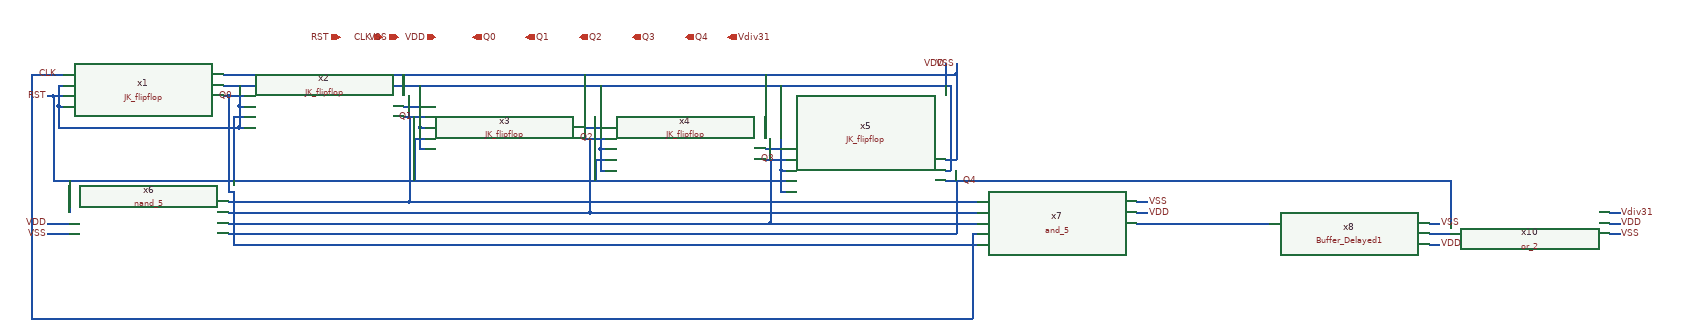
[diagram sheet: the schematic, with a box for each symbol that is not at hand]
v {xschem version=3.1.0 file_version=1.2
}
G {}
K {}
V {}
S {}
E {}
N 230 -20 260 -20 {
lab=Q0}
N 560 20 600 20 {
lab=Q1}
N 900 60 940 60 {
lab=Q2}
N 1240 100 1280 100 {
lab=Q3}
N 1270 120 1280 120 {
lab=VDD}
N 1270 120 1270 160 {
lab=VDD}
N 1270 160 1280 160 {
lab=VDD}
N 930 80 940 80 {
lab=VDD}
N 930 80 930 120 {
lab=VDD}
N 930 120 940 120 {
lab=VDD}
N 590 40 600 40 {
lab=VDD}
N 590 40 590 80 {
lab=VDD}
N 590 80 600 80 {
lab=VDD}
N 250 0 260 0 {
lab=VDD}
N 250 0 250 40 {
lab=VDD}
N 250 40 260 40 {
lab=VDD}
N -90 -40 -80 -40 {
lab=VDD}
N -90 -40 -90 0 {
lab=VDD}
N -90 0 -80 0 {
lab=VDD}
N 230 -40 1590 -40 {
lab=VDD}
N 1590 -40 1590 120 {
lab=VDD}
N 1580 120 1590 120 {
lab=VDD}
N 1270 -40 1270 120 {
lab=VDD}
N 930 -40 930 80 {
lab=VDD}
N 590 -40 590 40 {
lab=VDD}
N 250 -40 250 0 {
lab=VDD}
N -90 0 -90 20 {
lab=VDD}
N -90 20 -90 30 {
lab=VDD}
N -90 30 -90 40 {
lab=VDD}
N -80 40 250 40 {
lab=VDD}
N -100 -20 -80 -20 {
lab=RST}
N -100 -20 -100 140 {
lab=RST}
N -90 140 1280 140 {
lab=RST}
N 920 100 940 100 {
lab=RST}
N 920 100 920 140 {
lab=RST}
N 580 60 600 60 {
lab=RST}
N 580 60 580 140 {
lab=RST}
N 240 20 260 20 {
lab=RST}
N 240 20 240 140 {
lab=RST}
N 560 0 590 0 {
lab=VDD}
N 900 40 930 40 {
lab=VDD}
N 1240 80 1270 80 {
lab=VDD}
N 230 -60 1600 -60 {
lab=VSS}
N 1600 -60 1600 100 {
lab=VSS}
N 1580 100 1600 100 {
lab=VSS}
N 1240 -60 1240 60 {
lab=VSS}
N 900 -60 900 20 {
lab=VSS}
N 560 -60 560 -20 {
lab=VSS}
N -90 -60 -80 -60 {
lab=CLK}
N -110 -20 -100 -20 {
lab=RST}
N 1580 -80 1580 -70 {
lab=VDD}
N 1580 -70 1580 -40 {
lab=VDD}
N 1600 -80 1600 -60 {
lab=VSS}
N 1580 140 1610 140 {
lab=Q4}
N -100 140 -90 140 {
lab=RST}
N -90 40 -80 40 {
lab=VDD}
N 220 -60 230 -60 {
lab=VSS}
N 220 -40 230 -40 {
lab=VDD}
N 220 -20 230 -20 {
lab=Q0}
N 230 180 570 180 {
lab=Q1}
N 230 200 910 200 {
lab=Q2}
N 230 220 1250 220 {
lab=Q3}
N 230 240 1600 240 {
lab=Q4}
N 230 -20 230 160 {
lab=Q0}
N 570 20 570 180 {
lab=Q1}
N 910 60 910 200 {
lab=Q2}
N 1250 100 1250 220 {
lab=Q3}
N 1600 140 1600 240 {
lab=Q4}
N -70 140 -70 200 {
lab=RST}
N -110 220 -100 220 {
lab=VDD}
N -100 220 -70 220 {
lab=VDD}
N -110 240 -90 240 {
lab=VSS}
N -90 240 -70 240 {
lab=VSS}
N 570 180 1640 180 {
lab=Q1}
N 910 200 1640 200 {
lab=Q2}
N 1250 220 1640 220 {
lab=Q3}
N 230 160 240 160 {
lab=Q0}
N 240 160 240 260 {
lab=Q0}
N 240 260 1640 260 {
lab=Q0}
N -120 -60 -90 -60 {
lab=CLK}
N -140 -60 -120 -60 {
lab=CLK}
N -140 -60 -140 270 {
lab=CLK}
N 1630 240 1630 270 {
lab=CLK}
N 1630 240 1640 240 {
lab=CLK}
N 1940 220 1980 220 {
lab=#net1}
N 2160 220 2190 220 {
lab=#net1}
N 2490 240 2530 240 {
lab=#net2}
N 1610 140 2530 140 {
lab=Q4}
N 2530 140 2530 220 {
lab=Q4}
N 1950 180 1960 180 {
lab=VSS}
N 1940 200 1960 200 {
lab=VDD}
N 1940 180 1950 180 {
lab=VSS}
N 2840 240 2850 240 {
lab=VSS}
N 2830 220 2850 220 {
lab=VDD}
N 2830 240 2840 240 {
lab=VSS}
N 2830 200 2850 200 {
lab=Vdiv31}
N 1610 400 1630 400 {
lab=CLK}
N -140 400 1430 400 {
lab=CLK}
N -140 270 -140 400 {
lab=CLK}
N 1980 220 2160 220 {
lab=#net1}
N 1630 270 1630 400 {
lab=CLK}
N 1430 400 1610 400 {
lab=CLK}
N 2500 220 2510 220 {
lab=VSS}
N 2490 260 2510 260 {
lab=VDD}
N 2490 220 2500 220 {
lab=VSS}
C {JK_flipflop.sym} 70 -30 0 0 {name=x1}
C {JK_flipflop.sym} 410 10 0 0 {name=x2}
C {JK_flipflop.sym} 750 50 0 0 {name=x3}
C {JK_flipflop.sym} 1090 90 0 0 {name=x4}
C {JK_flipflop.sym} 1430 130 0 0 {name=x5}
C {devices/ipin.sym} 520 -130 0 0 {name=p2 lab=CLK}
C {devices/iopin.sym} 550 -130 0 0 {name=p3 lab=VSS
}
C {devices/iopin.sym} 620 -130 0 0 {name=p4 lab=VDD}
C {devices/opin.sym} 690 -130 0 0 {name=p18 lab=Q0}
C {devices/lab_pin.sym} -90 -60 0 0 {name=p15 sig_type=std_logic lab=CLK}
C {devices/lab_pin.sym} -110 -20 0 0 {name=p12 sig_type=std_logic lab=RST}
C {devices/lab_pin.sym} 1600 -80 1 0 {name=p6 sig_type=std_logic lab=VSS}
C {devices/lab_pin.sym} 1580 -80 1 0 {name=p7 sig_type=std_logic lab=VDD}
C {devices/opin.sym} 790 -130 0 0 {name=p1 lab=Q1}
C {devices/opin.sym} 890 -130 0 0 {name=p5 lab=Q2}
C {devices/opin.sym} 990 -130 0 0 {name=p8 lab=Q3}
C {devices/opin.sym} 1090 -130 0 0 {name=p9 lab=Q4}
C {devices/lab_pin.sym} 240 -20 1 0 {name=p10 sig_type=std_logic lab=Q0}
C {devices/lab_pin.sym} 580 20 1 0 {name=p11 sig_type=std_logic lab=Q1}
C {devices/lab_pin.sym} 920 60 1 0 {name=p13 sig_type=std_logic lab=Q2}
C {devices/lab_pin.sym} 1260 100 1 0 {name=p14 sig_type=std_logic lab=Q3}
C {devices/lab_pin.sym} 1610 140 2 0 {name=p16 sig_type=std_logic lab=Q4}
C {devices/lab_pin.sym} -110 240 0 0 {name=p17 sig_type=std_logic lab=VSS}
C {devices/lab_pin.sym} -110 220 0 0 {name=p19 sig_type=std_logic lab=VDD}
C {nand_5.sym} 80 200 2 0 {name=x6}
C {or_2.sym} 2680 220 2 1 {name=x10}
C {devices/lab_pin.sym} 1960 180 2 0 {name=p20 sig_type=std_logic lab=VSS}
C {devices/lab_pin.sym} 1960 200 2 0 {name=p21 sig_type=std_logic lab=VDD}
C {devices/lab_pin.sym} 2850 240 0 1 {name=p24 sig_type=std_logic lab=VSS}
C {devices/lab_pin.sym} 2850 220 0 1 {name=p25 sig_type=std_logic lab=VDD}
C {devices/opin.sym} 1170 -130 0 0 {name=p28 lab=Vdiv31}
C {devices/lab_pin.sym} 2850 200 0 1 {name=p29 sig_type=std_logic lab=Vdiv31}
C {and_5.sym} 1790 220 0 0 {name=x7}
C {devices/lab_pin.sym} 2510 220 2 0 {name=p22 sig_type=std_logic lab=VSS}
C {devices/lab_pin.sym} 2510 260 2 0 {name=p23 sig_type=std_logic lab=VDD}
C {devices/ipin.sym} 440 -130 0 0 {name=p26 lab=RST}
C {Buffer_Delayed1.sym} 2340 240 0 0 {name=x8}
